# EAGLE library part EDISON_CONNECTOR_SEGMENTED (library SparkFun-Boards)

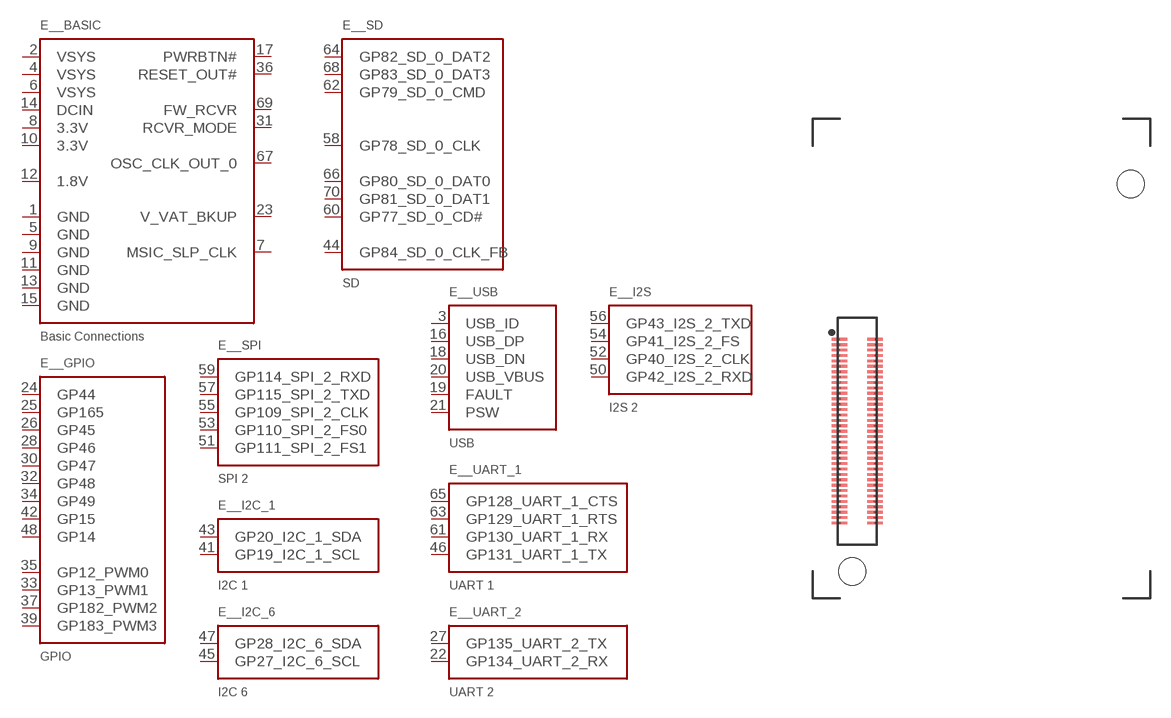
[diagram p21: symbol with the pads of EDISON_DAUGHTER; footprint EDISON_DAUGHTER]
Designator prefix E_; gates _BASIC=EDISON_CONNECTOR_BASE _GPIO=EDISON_CONNECTOR_GPIO _I2C_1=EDISON_CONNECTOR_I2C_1 _I2C_6=EDISON_CONNECTOR_I2C_6 _I2S=EDISON_CONNECTOR_I2S_2 _SD=EDISON_CONNECTOR_SD _SPI=EDISON_CONNECTOR_SPI_2 _UART_1=EDISON_CONNECTOR_UART_1 _UART_2=EDISON_CONNECTOR_UART_2 _USB=EDISON_CONNECTOR_USB

## EDISON_CONNECTOR_SEGMENTED  [EDISON_DAUGHTER]
1  _BASIC:GND
2  _BASIC:VSYS
3  _USB:USB_ID
4  _BASIC:VSYS
5  _BASIC:GND
6  _BASIC:VSYS
7  _BASIC:MSIC_SLP_CLK
8  _BASIC:3.3V
9  _BASIC:GND
10  _BASIC:3.3V
11  _BASIC:GND
12  _BASIC:1.8V
13  _BASIC:GND
14  _BASIC:DCIN
15  _BASIC:GND
16  _USB:USB_DP
17  _BASIC:PWRBTN#
18  _USB:USB_DN
19  _USB:FAULT
20  _USB:USB_VBUS
21  _USB:PSW
22  _UART_2:GP134_UART_2_RX
23  _BASIC:V_VAT_BKUP
24  _GPIO:GP44
25  _GPIO:GP165
26  _GPIO:GP45
27  _UART_2:GP135_UART_2_TX
28  _GPIO:GP46
30  _GPIO:GP47
31  _BASIC:RCVR_MODE
32  _GPIO:GP48
33  _GPIO:GP13_PWM1
34  _GPIO:GP49
35  _GPIO:GP12_PWM0
36  _BASIC:RESET_OUT#
37  _GPIO:GP182_PWM2
39  _GPIO:GP183_PWM3
41  _I2C_1:GP19_I2C_1_SCL
42  _GPIO:GP15
43  _I2C_1:GP20_I2C_1_SDA
44  _SD:GP84_SD_0_CLK_FB
45  _I2C_6:GP27_I2C_6_SCL
46  _UART_1:GP131_UART_1_TX
47  _I2C_6:GP28_I2C_6_SDA
48  _GPIO:GP14
50  _I2S:GP42_I2S_2_RXD
51  _SPI:GP111_SPI_2_FS1
52  _I2S:GP40_I2S_2_CLK
53  _SPI:GP110_SPI_2_FS0
54  _I2S:GP41_I2S_2_FS
55  _SPI:GP109_SPI_2_CLK
56  _I2S:GP43_I2S_2_TXD
57  _SPI:GP115_SPI_2_TXD
58  _SD:GP78_SD_0_CLK
59  _SPI:GP114_SPI_2_RXD
60  _SD:GP77_SD_0_CD#
61  _UART_1:GP130_UART_1_RX
62  _SD:GP79_SD_0_CMD
63  _UART_1:GP129_UART_1_RTS
64  _SD:GP82_SD_0_DAT2
65  _UART_1:GP128_UART_1_CTS
66  _SD:GP80_SD_0_DAT0
67  _BASIC:OSC_CLK_OUT_0
68  _SD:GP83_SD_0_DAT3
69  _BASIC:FW_RCVR
70  _SD:GP81_SD_0_DAT1

## Footprint EDISON_DAUGHTER (pad centres in mm)
smd 1.14 x 0.2: 1 1.98,19.17; 2 4.62,19.17; 3 1.98,18.77; 4 4.62,18.77; 5 1.98,18.37; 6 4.62,18.37; 7 1.98,17.97; 8 4.62,17.97; 9 1.98,17.57; 10 4.62,17.57; 11 1.98,17.17; 12 4.62,17.17; 13 1.98,16.77; 14 4.62,16.77; 15 1.98,16.37; 16 4.62,16.37; 17 1.98,15.97; 18 4.62,15.97; 19 1.98,15.57; 20 4.62,15.57; 21 1.98,15.17; 22 4.62,15.17; 23 1.98,14.77; 24 4.62,14.77; 25 1.98,14.37; 26 4.62,14.37; 27 1.98,13.97; 28 4.62,13.97; 29 1.98,13.57; 30 4.62,13.57; 31 1.98,13.17; 32 4.62,13.17; 33 1.98,12.77; 34 4.62,12.77; 35 1.98,12.37; 36 4.62,12.37; 37 1.98,11.97; 38 4.62,11.97; 39 1.98,11.57; 40 4.62,11.57; 41 1.98,11.17; 42 4.62,11.17; 43 1.98,10.77; 44 4.62,10.77; 45 1.98,10.37; 46 4.62,10.37; 47 1.98,9.97; 48 4.62,9.97; 49 1.98,9.57; 50 4.62,9.57; 51 1.98,9.17; 52 4.62,9.17; 53 1.98,8.77; 54 4.62,8.77; 55 1.98,8.37; 56 4.62,8.37; 57 1.98,7.97; 58 4.62,7.97; 59 1.98,7.57; 60 4.62,7.57; 61 1.98,7.17; 62 4.62,7.17; 63 1.98,6.77; 64 4.62,6.77; 65 1.98,6.37; 66 4.62,6.37; 67 1.98,5.97; 68 4.62,5.97; 69 1.98,5.57; 70 4.62,5.57
hole 2 at 23.53,30.67
hole 2 at 2.93,1.98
